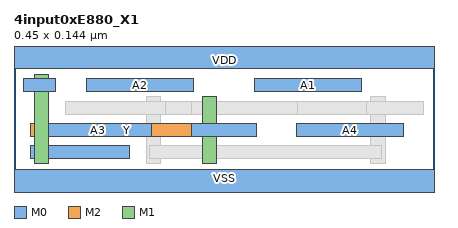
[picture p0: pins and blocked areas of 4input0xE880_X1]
MACRO 4input0xE880_X1
  CLASS CORE ;
  ORIGIN 0 0 ;
  FOREIGN 4input0xE880_X1 0 0 ;
  SIZE 0.4500 BY 0.1440 ;
  SYMMETRY X Y ;
  SITE coresite ;
  PIN A1
    DIRECTION INPUT ;
    USE SIGNAL ;
    PORT
      LAYER M0 ;
        RECT 0.2580 0.1010 0.3720 0.1150 ;
    END
  END A1
  PIN A2
    DIRECTION INPUT ;
    USE SIGNAL ;
    PORT
      LAYER M0 ;
        RECT 0.0780 0.1010 0.1920 0.1150 ;
    END
  END A2
  PIN A3
    DIRECTION INPUT ;
    USE SIGNAL ;
    PORT
      LAYER M0 ;
        RECT 0.0330 0.0530 0.1470 0.0670 ;
    END
  END A3
  PIN A4
    DIRECTION INPUT ;
    USE SIGNAL ;
    PORT
      LAYER M0 ;
        RECT 0.3030 0.0530 0.4170 0.0670 ;
    END
  END A4
  PIN Y
    DIRECTION OUTPUT ;
    USE SIGNAL ;
    PORT
      LAYER M2 ;
        RECT 0.0180 0.0530 0.2250 0.0670 ;
      LAYER M1 ;
        RECT 0.0220 0.0240 0.0370 0.1200 ;
        RECT 0.2020 0.0240 0.2170 0.0960 ;
      LAYER M0 ;
        RECT 0.1900 0.0530 0.2600 0.0670 ;
        RECT 0.0100 0.1010 0.0450 0.1150 ;
        RECT 0.0180 0.0290 0.1240 0.0430 ;
    END
  END Y
  PIN VDD
    DIRECTION INOUT ;
    USE POWER ;
    SHAPE ABUTMENT ;
    PORT
      LAYER M0 ;
        RECT 0.0000 0.1260 0.4500 0.1620 ;
    END
  END VDD
  PIN VSS
    DIRECTION INOUT ;
    USE GROUND ;
    SHAPE ABUTMENT ;
    PORT
      LAYER M0 ;
        RECT 0.0000 -0.0180 0.4500 0.0180 ;
    END
  END VSS
  OBS
    LAYER M2 ;
      RECT 0.1350 0.0770 0.4050 0.0910 ;
    LAYER V1 ;
      RECT 0.0230 0.0530 0.0370 0.0670 ;
      RECT 0.2030 0.0530 0.2170 0.0670 ;
      RECT 0.1430 0.0770 0.1570 0.0910 ;
      RECT 0.3830 0.0770 0.3970 0.0910 ;
    LAYER M1 ;
      RECT 0.1420 0.0240 0.1570 0.0960 ;
      RECT 0.3820 0.0240 0.3980 0.0960 ;
    LAYER V0 ;
      RECT 0.0230 0.1010 0.0370 0.1150 ;
      RECT 0.0230 0.0290 0.0370 0.0430 ;
      RECT 0.2030 0.0530 0.2170 0.0670 ;
      RECT 0.1430 0.0770 0.1570 0.0910 ;
      RECT 0.3830 0.0770 0.3970 0.0910 ;
    LAYER M0 ;
      RECT 0.1450 0.0290 0.3940 0.0430 ;
      RECT 0.0550 0.0770 0.1620 0.0910 ;
      RECT 0.1900 0.0770 0.3040 0.0910 ;
      RECT 0.3780 0.0770 0.4390 0.0910 ;
  END
END 4input0xE880_X1
